One B-rep face of a CAD part: STEP entity #105.
In plain terms, the planar face has unit normal (0, 0, 1).
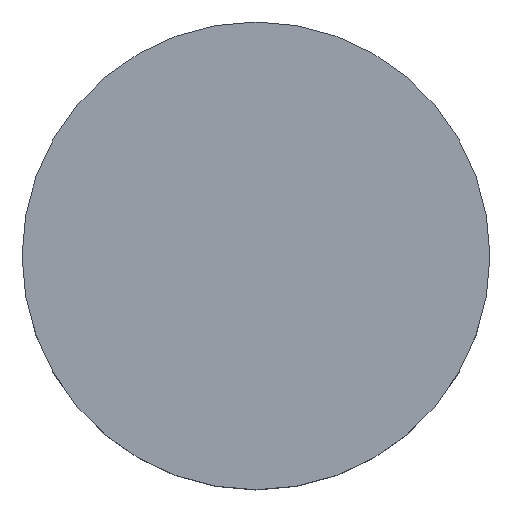
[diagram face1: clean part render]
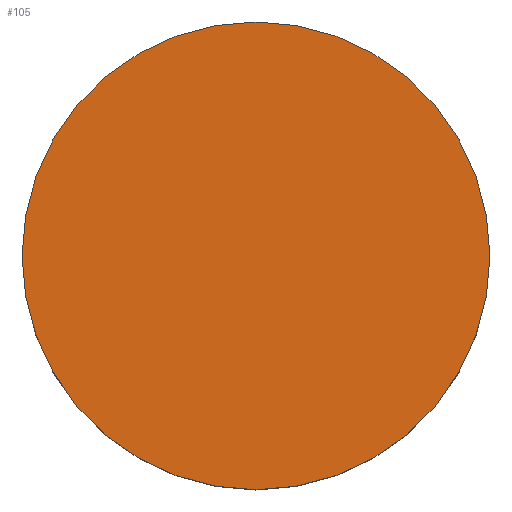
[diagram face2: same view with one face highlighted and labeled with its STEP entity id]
Its self-contained STEP definition (entity closure, numbers rounded to 3 decimals):
#21 = EDGE_CURVE('',#22,#22,#24,.T.);
#22 = VERTEX_POINT('',#23);
#23 = CARTESIAN_POINT('',(5.55,3.,15.05));
#24 = SURFACE_CURVE('',#25,(#30,#42),.PCURVE_S1.);
#25 = CIRCLE('',#26,1.55);
#26 = AXIS2_PLACEMENT_3D('',#27,#28,#29);
#27 = CARTESIAN_POINT('',(4.,3.,15.05));
#28 = DIRECTION('',(0.,0.,1.));
#29 = DIRECTION('',(1.,0.,-0.));
#30 = PCURVE('',#31,#36);
#31 = CYLINDRICAL_SURFACE('',#32,1.55);
#32 = AXIS2_PLACEMENT_3D('',#33,#34,#35);
#33 = CARTESIAN_POINT('',(4.,3.,14.2));
#34 = DIRECTION('',(0.,0.,1.));
#35 = DIRECTION('',(1.,0.,-0.));
#36 = DEFINITIONAL_REPRESENTATION('',(#37),#41);
#37 = LINE('',#38,#39);
#38 = CARTESIAN_POINT('',(0.,0.85));
#39 = VECTOR('',#40,1.);
#40 = DIRECTION('',(1.,0.));
#41 = ( GEOMETRIC_REPRESENTATION_CONTEXT(2) 
PARAMETRIC_REPRESENTATION_CONTEXT() REPRESENTATION_CONTEXT('2D SPACE',''
  ) );
#42 = PCURVE('',#43,#48);
#43 = PLANE('',#44);
#44 = AXIS2_PLACEMENT_3D('',#45,#46,#47);
#45 = CARTESIAN_POINT('',(4.,3.,15.05));
#46 = DIRECTION('',(0.,0.,1.));
#47 = DIRECTION('',(1.,0.,-0.));
#48 = DEFINITIONAL_REPRESENTATION('',(#49),#53);
#49 = CIRCLE('',#50,1.55);
#50 = AXIS2_PLACEMENT_2D('',#51,#52);
#51 = CARTESIAN_POINT('',(0.,0.));
#52 = DIRECTION('',(1.,0.));
#53 = ( GEOMETRIC_REPRESENTATION_CONTEXT(2) 
PARAMETRIC_REPRESENTATION_CONTEXT() REPRESENTATION_CONTEXT('2D SPACE',''
  ) );
#105 = ADVANCED_FACE('',(#106),#43,.T.);
#106 = FACE_BOUND('',#107,.T.);
#107 = EDGE_LOOP('',(#108));
#108 = ORIENTED_EDGE('',*,*,#21,.T.);
